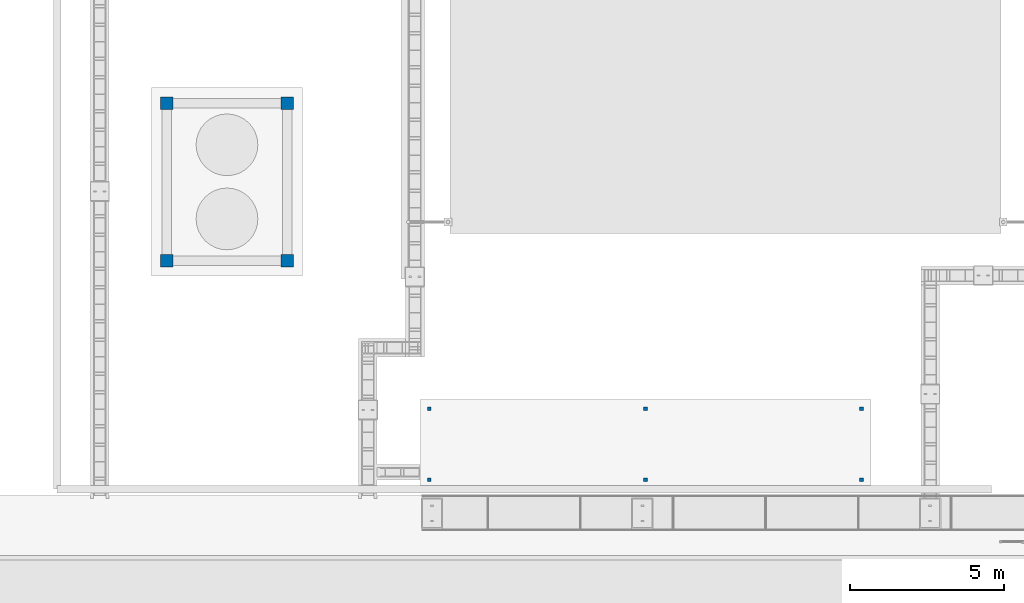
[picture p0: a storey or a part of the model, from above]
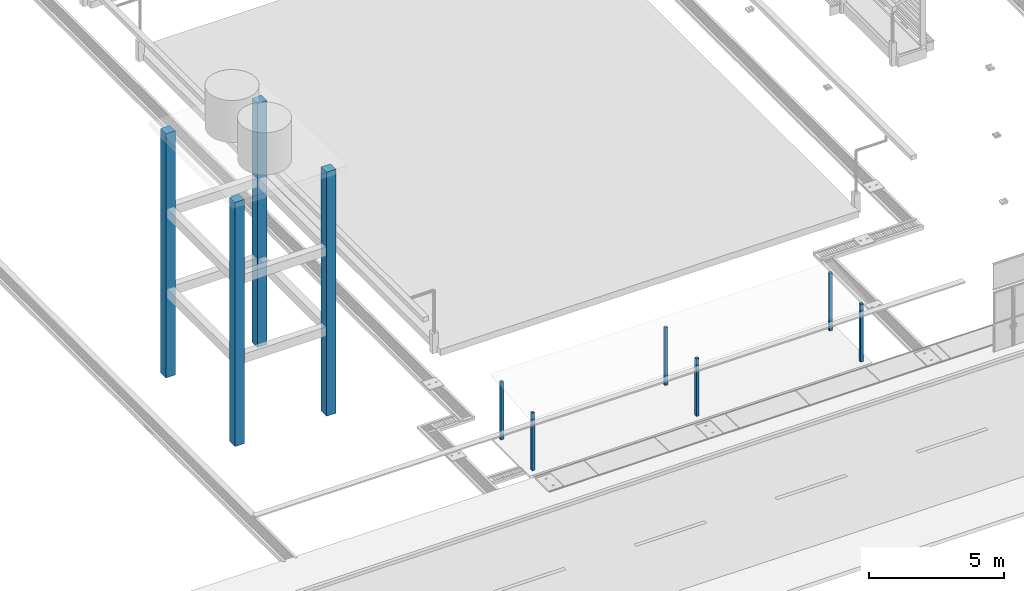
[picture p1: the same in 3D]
Properties of the parts of a building model (IFC2X3)

# File
Description: ViewDefinition [CoordinationView]
Time: 2026-11-03T16:17:56
Written by: IfcOpenShell 0.9.0post1+b5e509b
Made in: IfcOpenShell 0.9.0post1+b5e509b

# IfcBuildingStorey, NIVEL 1 (NPT +0.00)
In: Hogar de Refugio Temporal
Elevation: 0 m

# IfcBeam: Viga (188)
In: NIVEL 1 (NPT +0.00)
Pset_HogarRefugio - Categoria: Viga
Name | Grupo = Group | Material
2 x travesano | Losa deportiva | blanco
14 x arco | Losa deportiva | acero
133 x diag | Losa deportiva | acero
2 x viga_long | Losa deportiva | acero
8 x tanque_viga | Obras exteriores | concreto_gris
2 x columpio_viga | Obras exteriores | juego_rojo
9 x oc01_viga | Obras exteriores | estructura_acero
18 x oc01_correa | Obras exteriores | estructura_acero

# IfcBuildingElementProxy: Asta de banderas (3)
In: NIVEL 1 (NPT +0.00)
Pset_HogarRefugio - Grupo: Obras exteriores; Categoria: Asta de banderas
Group: Obras exteriores
Name | Material
2 x bandera | bandera_roja
bandera | bandera_blanca

# IfcBuildingElementProxy: Elemento (6)
In: NIVEL 1 (NPT +0.00)
Pset_HogarRefugio - Categoria: Elemento
Name | Grupo = Group | Material
Torus | Losa deportiva | linea
2 x Cylinder | Obras exteriores | negro
3 x Cylinder | Obras exteriores | aluminio_claro

# IfcBuildingElementProxy: Letras "HOGAR DE REFUGIO TEMPORAL", letrero
In: NIVEL 1 (NPT +0.00)
Pset_HogarRefugio - Grupo: Obras exteriores; Categoria: Letras "HOGAR DE REFUGIO TEMPORAL"; Material: aluminio_claro
Group: Obras exteriores

# IfcBuildingElementProxy: Losa deportiva y vía (111)
In: NIVEL 1 (NPT +0.00)
Pset_HogarRefugio - Categoria: Losa deportiva y vía
Name | Grupo = Group | Material
pista | Terreno | asfalto
92 x linea_carril | Terreno | linea
cancha | Losa deportiva | cancha
5 x linea_cancha | Losa deportiva | linea
2 x area | Losa deportiva | cancha_borde
6 x linea_area | Losa deportiva | linea
2 x tablero | Losa deportiva | blanco
2 x brazo | Losa deportiva | acero

# IfcBuildingElementProxy: Área verde (3)
In: NIVEL 1 (NPT +0.00)
Pset_HogarRefugio - Grupo: Pasto; Categoria: Área verde; Material: pasto
Group: Pasto
Name
pasto_jardinera_0
pasto_jardinera_1
pasto_jardinera_2

# IfcColumn: Columna (40)
In: NIVEL 1 (NPT +0.00)
Pset_HogarRefugio - Categoria: Columna
Name | Grupo = Group | Material
4 x poste_arco | Losa deportiva | blanco
2 x poste_basquet | Losa deportiva | acero
6 x poste_autos | Obras exteriores | acero
6 x poste_motos | Obras exteriores | acero
4 x tanque_col | Obras exteriores | concreto_gris
18 x oc01_columna | Obras exteriores | estructura_acero

# IfcColumn: Falsa columna (45)
In: NIVEL 1 (NPT +0.00)
Pset_HogarRefugio - Categoria: Falsa columna; Material: concreto_gris
Name | Grupo = Group
9 x oc01_falsa_columna | Obras exteriores
36 x falsa_columna | Drenaje

# IfcDistributionChamberElement: Tapa ciega de registro del colector (28)
In: NIVEL 1 (NPT +0.00)
Pset_HogarRefugio - Grupo: Drenaje; Categoria: Tapa ciega de registro del colector
Group: Drenaje
Name | Material
7 x tapa_junta | negro
7 x tapa_ciega | tapa_concreto
14 x tapa_asa | acero

# IfcDistributionChamberElement: Tapa de inspección (68)
In: NIVEL 1 (NPT +0.00)
Pset_HogarRefugio - Grupo: Drenaje; Categoria: Tapa de inspección
Group: Drenaje
Name | Material
17 x tapa_insp_junta | negro
17 x tapa_inspeccion | tapa_inspeccion
34 x tapa_insp_asa | acero

# IfcDoor: Puerta / portón (35)
In: NIVEL 1 (NPT +0.00)
Pset_HogarRefugio - Grupo: Obras exteriores; Categoria: Puerta / portón
Group: Obras exteriores
Name | Material
2 x oe01_porton_peatonal_plancha | plancha_metalica
10 x oe01_porton_peatonal_m | negro
2 x oe01_porton_peatonal_manija | acero
oe01_puerta_plancha | plancha_metalica
5 x oe01_puerta_m | negro
oe01_puerta_manija | acero
2 x oe01_porton_vehicular_plancha | plancha_metalica
10 x oe01_porton_vehicular_m | negro
2 x oe01_porton_vehicular_manija | acero

# IfcFlowFitting: Rejilla metálica de cuneta y sumidero, rejillas_cunetas
In: NIVEL 1 (NPT +0.00)
Pset_HogarRefugio - Grupo: Drenaje; Categoria: Rejilla metálica de cuneta y sumidero; Material: galvanizado
Group: Drenaje

# IfcFlowSegment: Canaleta (27)
In: NIVEL 1 (NPT +0.00)
Pset_HogarRefugio - Categoria: Canaleta
Name | Grupo = Group | Material
2 x E-01_canaleta | E-01 | canaleta_galv
2 x E-02_canaleta | E-02 | canaleta_galv
2 x E-03_canaleta | E-03 | canaleta_galv
2 x E-04_canaleta | E-04 | canaleta_galv
2 x E-05_canaleta | E-05 | canaleta_galv
2 x E-06_canaleta | E-06 | canaleta_galv
2 x E-08_canaleta | E-08 | canaleta_galv
2 x E-07_canaleta | E-07 | canaleta_galv
2 x E-09_canaleta | E-09 | canaleta_galv
9 x oc01_canaleta | Obras exteriores | galvanizado

# IfcFlowSegment: Colector frontal b=0.80 (losa-vereda) (23)
In: NIVEL 1 (NPT +0.00)
Pset_HogarRefugio - Grupo: Drenaje; Categoria: Colector frontal b=0.80 (losa-vereda)
Group: Drenaje
Name | Material
colector_losa | concreto_cuneta
2 x junta_colector | negro
20 x junta_losa | negro

# IfcFlowSegment: Cuneta de concreto b=0.40 (2)
In: NIVEL 1 (NPT +0.00)
Pset_HogarRefugio - Grupo: Drenaje; Categoria: Cuneta de concreto b=0.40
Group: Drenaje
Name | Material
cunetas_muros | concreto_cuneta
cunetas_fondo | cuneta_fondo

# IfcFlowSegment: Montante PVC 4" (189)
In: NIVEL 1 (NPT +0.00)
Pset_HogarRefugio - Grupo: Obras exteriores; Categoria: Montante PVC 4"
Group: Obras exteriores
Name | Material
36 x montante_boquilla | pvc
36 x montante_desvio | pvc
36 x montante_bajada | pvc
72 x montante_abrazadera | galvanizado
9 x oc01_bajada | pvc

# IfcFlowTerminal: Sumidero con rejilla (30)
In: NIVEL 1 (NPT +0.00)
Pset_HogarRefugio - Grupo: Drenaje; Categoria: Sumidero con rejilla; Material: cuneta_fondo
Group: Drenaje

# IfcFurnishingElement: Mobiliario exterior / juegos (211)
In: NIVEL 1 (NPT +0.00)
Pset_HogarRefugio - Grupo: Obras exteriores; Categoria: Mobiliario exterior / juegos
Group: Obras exteriores
Name | Material
14 x banca_base | concreto_gris
14 x banca_asiento | madera
5 x balancin_base | juego_azul
5 x balancin_tabla | juego_rojo
10 x balancin_manija | plastico_amarillo
2 x tobogan_escalera | juego_azul
4 x tobogan_poste | juego_azul
5 x peldano | acero
tobogan_plataforma | juego_rojo
2 x baranda | juego_azul
resbaladera | plastico_amarillo
2 x resbaladera_borde | plastico_amarillo
8 x columpio_pata | juego_rojo
4 x columpio_asiento | plastico_amarillo
8 x cadena | acero
54 x oc01_celosia | madera
45 x oc01_asiento | madera
27 x oc01_pata | estructura_acero

# IfcRoof: Cobertura (12)
In: NIVEL 1 (NPT +0.00)
Pset_HogarRefugio - Grupo: Obras exteriores; Categoria: Cobertura
Group: Obras exteriores
Name | Material
techo_autos | calamina_y
techo_motos | calamina_y
tobogan_techo | juego_verde
3 x oc01_cobertura_aluzinc | calamina_y
6 x oc01_cobertura_aluzinc | calamina_x

# IfcSlab: Piso / losa (12)
In: NIVEL 1 (NPT +0.00)
PredefinedType: FLOOR
Pset_HogarRefugio - Categoria: Piso / losa
Name | Grupo = Group | Material
vereda_ext | Terreno | vereda
vereda_otra | Terreno | vereda
sardinel | Terreno | blanco
losa_autos | Obras exteriores | concreto_gris
losa_motos | Obras exteriores | concreto_gris
tanque_losa | Obras exteriores | concreto_gris
asta_base | Obras exteriores | concreto_gris
juegos_arena | Obras exteriores | arena
4 x juegos_sardinel | Obras exteriores | concreto_gris

# IfcWall: Muro (21)
In: NIVEL 1 (NPT +0.00)
Pset_HogarRefugio - Categoria: Muro
Name | Grupo = Group | Material
E-01_zocalo | E-01 | concreto_gris
E-02_zocalo | E-02 | concreto_gris
E-03_zocalo | E-03 | concreto_gris
E-04_zocalo | E-04 | concreto_gris
E-05_zocalo | E-05 | concreto_gris
E-06_zocalo | E-06 | concreto_gris
E-08_zocalo | E-08 | concreto_gris
E-07_zocalo | E-07 | concreto_gris
E-09_zocalo | E-09 | concreto_gris
oe01_zocalo | Obras exteriores | concreto_gris
5 x cerco_remate | Obras exteriores | concreto_gris
3 x jardinera | Obras exteriores | concreto_gris
3 x jardinera_tierra | Obras exteriores | tierra_jardinera

# IfcWindow: Ventana / paño metálico (18)
In: NIVEL 1 (NPT +0.00)
Pset_HogarRefugio - Grupo: Obras exteriores; Categoria: Ventana / paño metálico
Group: Obras exteriores
Name | Material
oe01_celosia1 | plancha_metalica
2 x oe01_celosia1_marco | negro
oe01_ventana | plancha_metalica
2 x oe01_ventana_marco | negro
oe01_celosia3 | plancha_metalica
2 x oe01_celosia3_marco | negro
3 x oe01_celosia4 | plancha_metalica
6 x oe01_celosia4_marco | negro
